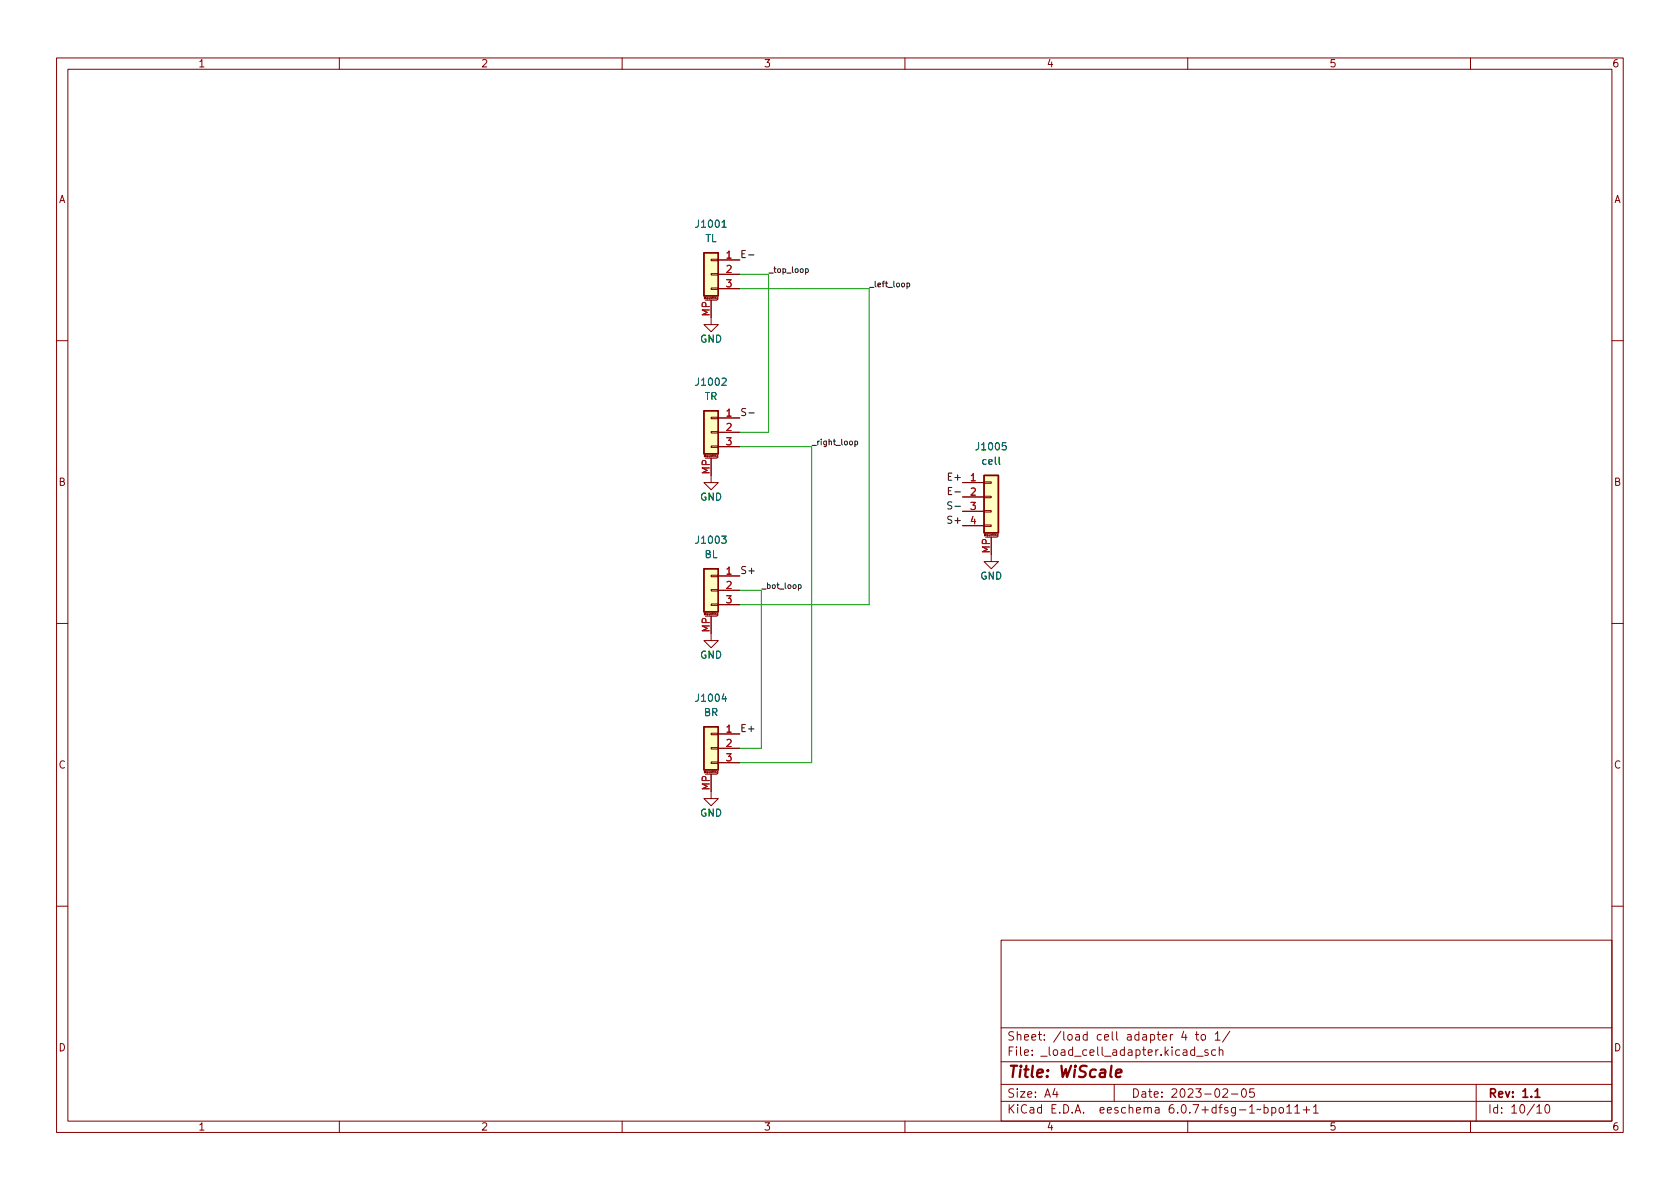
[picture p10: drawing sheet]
<svg xmlns="http://www.w3.org/2000/svg" width="297mm" height="210mm" viewBox="0 0 297 210" stroke-linecap="round" stroke-linejoin="round" font-family="sans-serif">
<defs><g id="words">
<text font-size="2.8" fill="#840000" x="178" y="190.6">Title: WiScale</text>
<g font-size="2.1" fill="#840000">
<text x="178" y="184">Sheet: /load cell adapter 4 to 1/</text>
<text x="178" y="186.7">File: _load_cell_adapter.kicad_sch</text>
<text x="178" y="196.9">KiCad E.D.A. eeschema 6.0.7+dfsg-1~bpo11+1</text>
<text x="178" y="194.1">Size: A4</text>
<text x="200" y="194.1">Date: 2023-02-05</text>
<text x="263" y="194.1">Rev: 1.1</text>
<text x="263" y="196.9">Id: 10/10</text>
</g>
<g font-size="1.8" fill="#840000">
<text x="35" y="11.9">1</text>
<text x="85" y="11.9">2</text>
<text x="135" y="11.9">3</text>
<text x="185" y="11.9">4</text>
<text x="235" y="11.9">5</text>
<text x="285" y="11.9">6</text>
<text x="10.3" y="35.9">A</text>
<text x="285.3" y="35.9">A</text>
<text x="10.3" y="85.9">B</text>
<text x="285.3" y="85.9">B</text>
<text x="10.3" y="135.9">C</text>
<text x="285.3" y="135.9">C</text>
<text x="10.3" y="185.9">D</text>
<text x="285.3" y="185.9">D</text>
<text x="35" y="199.9">1</text>
<text x="85" y="199.9">2</text>
<text x="135" y="199.9">3</text>
<text x="185" y="199.9">4</text>
<text x="235" y="199.9">5</text>
<text x="285" y="199.9">6</text>
</g>
<g font-size="1.8" fill="#006464">
<text x="123.3" y="40.3">J1001</text>
<text x="124.6" y="42.8">TL</text>
<text x="123.8" y="60.6">GND</text>
<text x="123.3" y="68.2">J1002</text>
<text x="124.6" y="70.7">TR</text>
<text x="172.8" y="79.6">J1005</text>
<text x="173.8" y="82.2">cell</text>
<text x="123.8" y="88.5">GND</text>
<text x="123.3" y="96.1">J1003</text>
<text x="124.6" y="98.7">BL</text>
<text x="173.3" y="102.5">GND</text>
<text x="123.8" y="116.5">GND</text>
<text x="123.3" y="124.1">J1004</text>
<text x="124.5" y="126.6">BR</text>
<text x="123.8" y="144.4">GND</text>
</g>
<g font-size="1.8" fill="#a90000">
<text x="128.4" y="45.7">1</text>
<text x="128.4" y="48.3">2</text>
<text x="128.4" y="50.8">3</text>
<text x="125.5" y="55.9" transform="rotate(-90 125.5 55.9)">MP</text>
<text x="128.4" y="73.7">1</text>
<text x="128.4" y="76.2">2</text>
<text x="125.5" y="83.9" transform="rotate(-90 125.5 83.9)">MP</text>
<text x="128.4" y="78.7">3</text>
<text x="171.6" y="85.1">1</text>
<text x="171.6" y="87.6">2</text>
<text x="171.6" y="90.2">3</text>
<text x="171.6" y="92.7">4</text>
<text x="128.4" y="101.6">1</text>
<text x="175" y="97.8" transform="rotate(-90 175 97.8)">MP</text>
<text x="128.4" y="104.1">2</text>
<text x="128.4" y="106.7">3</text>
<text x="125.5" y="111.8" transform="rotate(-90 125.5 111.8)">MP</text>
<text x="128.4" y="129.5">1</text>
<text x="128.4" y="132.1">2</text>
<text x="128.4" y="134.6">3</text>
<text x="125.5" y="139.8" transform="rotate(-90 125.5 139.8)">MP</text>
</g>
<g font-size="1.8" fill="#0f0f0f">
<text x="130.8" y="45.6">E-</text>
<text x="168" y="85">E+</text>
<text x="168" y="92.6">S+</text>
<text x="130.8" y="101.5">S+</text>
<text x="130.8" y="129.4">E+</text>
</g>
<g font-size="1.4" fill="#0f0f0f">
<text x="135.9" y="48.2">_top_loop</text>
<text x="153.7" y="50.8">_left_loop</text>
<text x="143.5" y="78.7">_right_loop</text>
<text x="134.6" y="104.1">_bot_loop</text>
</g>
<g font-size=".5" fill="#840000">
<text x="124.5" y="52.9">Mounting</text>
<text x="124.5" y="80.8">Mounting</text>
<text x="174.1" y="94.8">Mounting</text>
<text x="124.5" y="108.8">Mounting</text>
<text x="124.5" y="136.7">Mounting</text>
</g>
</g></defs>
<g fill="none" stroke="#840000" stroke-width=".18">
<path d="M10 10.2h277v190.1h-277zM12 12.2h273v186.1h-273zM60 10.2v2M110 10.2v2M160 10.2v2M210 10.2v2M260 10.2v2M124.7 53.1h2M125.7 50.9h1.3v.3h-1.3zM125.7 48.4h1.3v.2h-1.3zM125.7 45.8h1.3v.3h-1.3zM125.7 53.1v4.3h1.3l-1.3 1.3-1.2-1.3h1.2"/>
<path d="M126.9 52.6v.3l-.1 .1M126.9 52.6l-.2 .1 .1 .2h.1M127 46h3.8M127 48.5h3.8M127 51h3.8M10 60.2h2M125.7 78.9h1.3v.2h-1.3zM125.7 76.3h1.3v.3h-1.3zM125.7 73.8h1.3v.2h-1.3zM127 73.9h3.8M127 76.4h3.8M127 79h3.8"/>
<path d="M285 60.2h2M124.7 81h2M125.7 81v4.3h1.3l-1.3 1.3-1.2-1.3h1.2M126.9 80.6v.3h-.1M126.9 80.6h-.2l.1 .2h.1M170.2 85.3h3.8M170.2 87.9h3.8M170.2 90.4h3.8M170.2 93h3.8M174 92.8h1.3v.3h-1.3zM174 90.3h1.3v.2h-1.3zM174 87.8h1.3v.2h-1.3z"/>
<path d="M174 85.2h1.3v.3h-1.3zM174.2 95h2.1M175.3 95v4.3h-1.3l1.3 1.3 1.2-1.3h-1.2M176.4 94.8l-.1-.1v-.2h.1v.3l-.1 .1M10 110.2h2M124.7 109h2M125.7 106.8h1.3v.3h-1.3zM125.7 104.3h1.3v.2h-1.3zM125.7 101.7h1.3v.3h-1.3zM125.7 109v4.3h1.3l-1.3 1.2-1.2-1.2h1.2M126.9 108.7h-.1v-.2h.1v.3l-.1 .1M127 101.8h3.8"/>
<path d="M127 104.4h3.8M127 106.9h3.8M285 110.2h2M124.7 136.9h2M125.7 134.7h1.3v.3h-1.3zM125.7 132.2h1.3v.3h-1.3zM125.7 129.7h1.3v.2h-1.3zM125.7 136.9v4.3h1.3l-1.3 1.3-1.2-1.3h1.2M126.9 136.7h-.1v-.2l.1-.1v.3l-.1 .1M127 129.8h3.8M127 132.3h3.8M127 134.9h3.8"/>
<path d="M10 160.2h2M177 166.3h108v32h-108zM285 160.2h2M60 198.3v2M110 198.3v2M160 198.3v2M177 194.8h108M177 191.8h108M177 187.8h108M177 181.8h108M186.5 192.5l-.4 1h1M186.9 193v1"/>
<path d="M197 191.8v3M209.3 182.4l-.4 1h1M209.6 182.9v1M210 198.3v2M211.2 185.7l-.4-.1-.3 .3v.4l.1 .3h.6M211.2 185.1v1.5M211.4 182.9h.5M211.6 182.4v1.3l.3 .2M211.6 186.8h1.1M212.4 183.1l.2-.2 .5 .2v.5l-.1 .3h-.4l-.2-.1zM213.6 185.7l-.4-.1-.2 .2 .1 .3 .5 .1v.4h-.6M214.9 182.9l.4-.5v1.5"/>
<path d="M214.9 183.9h.8M214.9 185.7l-.4-.1-.3 .3v.4l.2 .3h.5M215.6 185.8l.2-.2 .3 .1 .1 .9M215.6 185.1v1.5M216.2 192.7l.6-.2 .2 .2 .1 .3-1 1h1M217.4 182.4l-1.3 1.9M217.7 193.5h1.2M219.7 192.6l.2-.1a.81 .81 0 0 1 .5 .7 .81 .81 0 0 1-.3 .8h-.1a.81 .81 0 0 1-.6-.6 .81 .81 0 0 1 .3-.8zM221.7 192.5h-.7l-.1 .7 .2-.1 .5 .1 .2 .2-.1 .5-.2 .1-.6-.1M223.5 195.9l.4-.1 .3 .3v.4l-.1 .3h-.6M223.5 195.3v1.5M224.9 195.9l.4-.1 .3 .3v.4l-.2 .3h-.5"/>
<path d="M224.9 195.8v1.5M226.3 195.9l.3-.1 .3 .3v.4l-.3 .3h-.3l-.2-.3v-.4zM227.5 195.8l.4-.5v1.5M227.5 196.8h.9M228.9 195.8l.5-.5v1.5M228.9 196.8h.9M230.4 196.3h1.2M231 195.7v1.1M232.2 195.8l.4-.5v1.5M232.2 196.8h.9M260 198.3v2M261 191.8v6.5"/>
<path d="M271.7 195.8l.5-.5v1.5M271.7 196.8h.9M273.4 195.4l.1-.1a.8 .8 0 0 1 .5 .8 .8 .8 0 0 1-.5 .7 .99 .99 0 0 1-.1-1.4z"/>
</g>
<path d="M271.4 193l.4-.5v1.5M271.4 194h.9" fill="none" stroke="#840000" stroke-width=".3"/>
<path d="M197.3 189.8l1-.2-.1-.4-.1-.1-.6 .1-.2 1 .2 .3 .6-.1" fill="none" stroke="#840000" stroke-width=".4"/>
<g fill="#ffffc2" stroke="#ffffc2" stroke-width=".18">
<path d="M124.5 128.5h2.5v7.6h-2.5z"/>
<path d="M124.5 100.6h2.5v7.6h-2.5z"/>
<path d="M124.5 72.6h2.5v7.7h-2.5z"/>
<path d="M174 84.1h2.5v10.1h-2.5z"/>
<path d="M124.5 44.7h2.5v7.6h-2.5z"/>
</g>
<path d="M124.5 44.7h2.5v7.6h-2.5zM124.5 72.6h2.5v7.7h-2.5zM174 84.1h2.5v10.1h-2.5zM124.5 100.6h2.5v7.6h-2.5zM124.5 128.5h2.5v7.6h-2.5z" fill="none" stroke="#840000" stroke-width=".25"/>
<path d="M127.7 40.2h.7" fill="none" stroke="#006464" stroke-width=".18"/>
<g fill="none" stroke="#0f0f0f" stroke-width=".18">
<path d="M132.3 45.1h1M142.4 47.6l.3-.1 .2 .2-.1 .4h-.4M142.4 47.5v1M160.4 50.1h.3l.1 .1-.1 .5h-.3M160.4 50.1v1M131.9 72.3l-.5-.1-.3 .3 .1 .3 .6 .2v.4l-.2 .1-.5-.1M132.4 73h1M151.2 78h.2l.2 .2-.1 .4h-.3M151.2 78v1M167.7 86.8h.4M168.3 86.2h-.6v1.3h.6M168.3 88.8l-.5-.1-.2 .2v.3l.6 .3 .1 .3-.3 .2-.4-.1"/>
<path d="M168.8 87h1M168.8 89.5h1M141.2 103.4h.3l.1 .2v.4h-.4M141.2 103.4v1"/>
</g>
<path d="M130.8 51h22.9v55.9h-22.9M130.8 48.5h5.1v27.9h-5.1M130.8 79h12.7v55.9h-12.7M130.8 104.4h3.8v27.9h-3.8" fill="none" stroke="#009600" stroke-width=".18"/>
<use href="#words"/>
</svg>
